One B-rep face of a CAD part: STEP entity #184.
In plain terms, the planar face has unit normal (1, 0, 0).
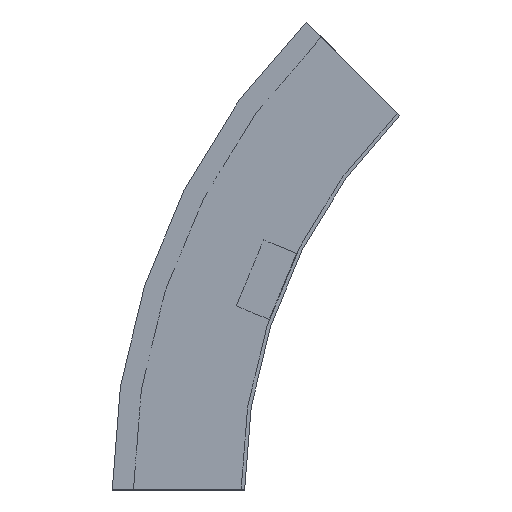
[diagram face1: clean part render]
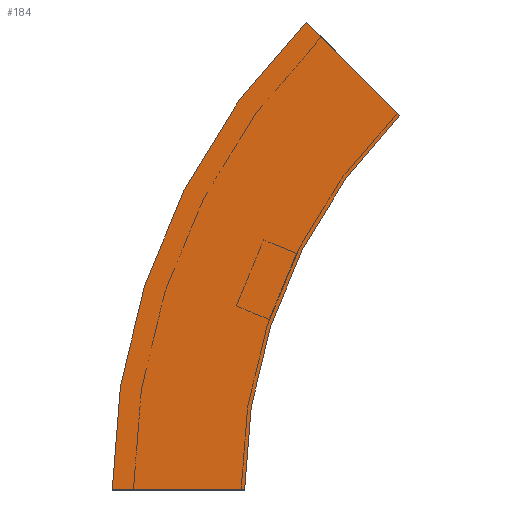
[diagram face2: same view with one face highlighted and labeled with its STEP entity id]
Its self-contained STEP definition (entity closure, numbers rounded to 3 decimals):
#29 = ORIENTED_EDGE ( 'NONE', *, *, #374, .T. ) ;
#35 = CARTESIAN_POINT ( 'NONE',  ( 0., -34.835, 265.165 ) ) ;
#36 = CIRCLE ( 'NONE', #114, 375. ) ;
#37 = LINE ( 'NONE', #257, #513 ) ;
#57 = DIRECTION ( 'NONE',  ( 1., 0., 0. ) ) ;
#58 = CARTESIAN_POINT ( 'NONE',  ( 0., 0., 0. ) ) ;
#79 = EDGE_CURVE ( 'NONE', #220, #163, #36, .T. ) ;
#103 = CARTESIAN_POINT ( 'NONE',  ( 0., 75., 0. ) ) ;
#105 = PLANE ( 'NONE',  #137 ) ;
#114 = AXIS2_PLACEMENT_3D ( 'NONE', #260, #434, #428 ) ;
#137 = AXIS2_PLACEMENT_3D ( 'NONE', #58, #57, #229 ) ;
#142 = DIRECTION ( 'NONE',  ( 0., 0.707, 0.707 ) ) ;
#148 = ORIENTED_EDGE ( 'NONE', *, *, #481, .F. ) ;
#163 = VERTEX_POINT ( 'NONE', #35 ) ;
#177 = VERTEX_POINT ( 'NONE', #317 ) ;
#184 = ADVANCED_FACE ( 'NONE', ( #490 ), #105, .T. ) ;
#219 = LINE ( 'NONE', #383, #435 ) ;
#220 = VERTEX_POINT ( 'NONE', #103 ) ;
#221 = EDGE_CURVE ( 'NONE', #446, #177, #447, .T. ) ;
#229 = DIRECTION ( 'NONE',  ( 0., 0., -1. ) ) ;
#252 = EDGE_LOOP ( 'NONE', ( #400, #148, #371, #29 ) ) ;
#257 = CARTESIAN_POINT ( 'NONE',  ( 0., 0., 0. ) ) ;
#260 = CARTESIAN_POINT ( 'NONE',  ( 0., -300., 0. ) ) ;
#271 = CARTESIAN_POINT ( 'NONE',  ( 0., -300., 0. ) ) ;
#317 = CARTESIAN_POINT ( 'NONE',  ( 0., -87.868, 212.132 ) ) ;
#371 = ORIENTED_EDGE ( 'NONE', *, *, #221, .F. ) ;
#374 = EDGE_CURVE ( 'NONE', #446, #220, #37, .T. ) ;
#383 = CARTESIAN_POINT ( 'NONE',  ( 0., -87.868, 212.132 ) ) ;
#400 = ORIENTED_EDGE ( 'NONE', *, *, #79, .T. ) ;
#427 = DIRECTION ( 'NONE',  ( 1., 0., 0. ) ) ;
#428 = DIRECTION ( 'NONE',  ( 0., 1., 0. ) ) ;
#434 = DIRECTION ( 'NONE',  ( 1., 0., 0. ) ) ;
#435 = VECTOR ( 'NONE', #142, 1000. ) ;
#446 = VERTEX_POINT ( 'NONE', #562 ) ;
#447 = CIRCLE ( 'NONE', #560, 300. ) ;
#481 = EDGE_CURVE ( 'NONE', #177, #163, #219, .T. ) ;
#490 = FACE_OUTER_BOUND ( 'NONE', #252, .T. ) ;
#505 = DIRECTION ( 'NONE',  ( 0., 1., 0. ) ) ;
#513 = VECTOR ( 'NONE', #505, 1000. ) ;
#549 = DIRECTION ( 'NONE',  ( 0., 1., 0. ) ) ;
#560 = AXIS2_PLACEMENT_3D ( 'NONE', #271, #427, #549 ) ;
#562 = CARTESIAN_POINT ( 'NONE',  ( 0., 0., 0. ) ) ;
